VERSION 5.7 ;
  NOWIREEXTENSIONATPIN ON ;
  DIVIDERCHAR "/" ;
  BUSBITCHARS "[]" ;
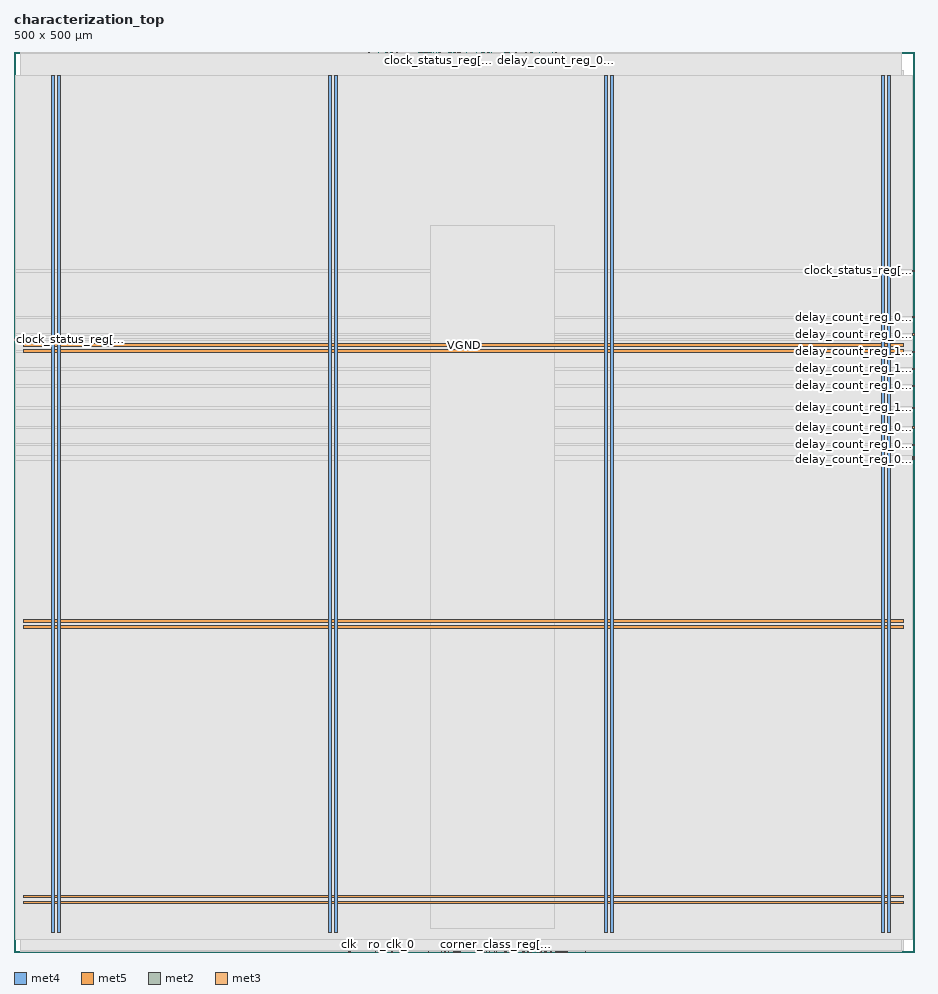
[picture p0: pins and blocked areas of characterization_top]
MACRO characterization_top
  CLASS BLOCK ;
  FOREIGN characterization_top ;
  ORIGIN 0.000 0.000 ;
  SIZE 500.000 BY 500.000 ;
  PIN VGND
    DIRECTION INOUT ;
    USE GROUND ;
    PORT
      LAYER met4 ;
        RECT 24.340 10.640 25.940 487.120 ;
    END
    PORT
      LAYER met4 ;
        RECT 177.940 10.640 179.540 487.120 ;
    END
    PORT
      LAYER met4 ;
        RECT 331.540 10.640 333.140 487.120 ;
    END
    PORT
      LAYER met4 ;
        RECT 485.140 10.640 486.740 487.120 ;
    END
    PORT
      LAYER met5 ;
        RECT 5.520 30.030 494.040 31.630 ;
    END
    PORT
      LAYER met5 ;
        RECT 5.520 183.210 494.040 184.810 ;
    END
    PORT
      LAYER met5 ;
        RECT 5.520 336.390 494.040 337.990 ;
    END
  END VGND
  PIN VPWR
    DIRECTION INOUT ;
    USE POWER ;
    PORT
      LAYER met4 ;
        RECT 21.040 10.640 22.640 487.120 ;
    END
    PORT
      LAYER met4 ;
        RECT 174.640 10.640 176.240 487.120 ;
    END
    PORT
      LAYER met4 ;
        RECT 328.240 10.640 329.840 487.120 ;
    END
    PORT
      LAYER met4 ;
        RECT 481.840 10.640 483.440 487.120 ;
    END
    PORT
      LAYER met5 ;
        RECT 5.520 26.730 494.040 28.330 ;
    END
    PORT
      LAYER met5 ;
        RECT 5.520 179.910 494.040 181.510 ;
    END
    PORT
      LAYER met5 ;
        RECT 5.520 333.090 494.040 334.690 ;
    END
  END VPWR
  PIN busy
    DIRECTION OUTPUT ;
    USE SIGNAL ;
    ANTENNADIFFAREA 0.702900 ;
    PORT
      LAYER met2 ;
        RECT 207.090 499.720 207.370 500.000 ;
    END
  END busy
  PIN clk
    DIRECTION INPUT ;
    USE SIGNAL ;
    ANTENNAGATEAREA 0.852000 ;
    PORT
      LAYER met2 ;
        RECT 185.930 0.000 186.210 0.280 ;
    END
  END clk
  PIN clk_bad_duty
    DIRECTION INPUT ;
    USE SIGNAL ;
    ANTENNAGATEAREA 0.213000 ;
    PORT
      LAYER met2 ;
        RECT 243.890 0.000 244.170 0.280 ;
    END
  END clk_bad_duty
  PIN clk_fast
    DIRECTION INPUT ;
    USE SIGNAL ;
    ANTENNAGATEAREA 0.213000 ;
    PORT
      LAYER met2 ;
        RECT 231.930 499.720 232.210 500.000 ;
    END
  END clk_fast
  PIN clk_slow
    DIRECTION INPUT ;
    USE SIGNAL ;
    ANTENNAGATEAREA 0.213000 ;
    PORT
      LAYER met2 ;
        RECT 244.810 0.000 245.090 0.280 ;
    END
  END clk_slow
  PIN clk_stuck_high
    DIRECTION INPUT ;
    USE SIGNAL ;
    ANTENNAGATEAREA 0.213000 ;
    PORT
      LAYER met2 ;
        RECT 230.090 499.720 230.370 500.000 ;
    END
  END clk_stuck_high
  PIN clk_stuck_low
    DIRECTION INPUT ;
    USE SIGNAL ;
    ANTENNAGATEAREA 0.196500 ;
    PORT
      LAYER met2 ;
        RECT 242.970 499.720 243.250 500.000 ;
    END
  END clk_stuck_low
  PIN clock_status_reg[0]
    DIRECTION OUTPUT ;
    USE SIGNAL ;
    ANTENNADIFFAREA 0.702900 ;
    PORT
      LAYER met2 ;
        RECT 245.730 0.000 246.010 0.280 ;
    END
  END clock_status_reg[0]
  PIN clock_status_reg[1]
    DIRECTION OUTPUT ;
    USE SIGNAL ;
    ANTENNADIFFAREA 0.702900 ;
    PORT
      LAYER met2 ;
        RECT 235.610 499.720 235.890 500.000 ;
    END
  END clock_status_reg[1]
  PIN clock_status_reg[2]
    DIRECTION OUTPUT ;
    USE SIGNAL ;
    ANTENNADIFFAREA 0.702900 ;
    PORT
      LAYER met2 ;
        RECT 246.650 0.000 246.930 0.280 ;
    END
  END clock_status_reg[2]
  PIN clock_status_reg[3]
    DIRECTION OUTPUT ;
    USE SIGNAL ;
    ANTENNADIFFAREA 0.702900 ;
    PORT
      LAYER met2 ;
        RECT 229.170 499.720 229.450 500.000 ;
    END
  END clock_status_reg[3]
  PIN clock_status_reg[4]
    DIRECTION OUTPUT ;
    USE SIGNAL ;
    ANTENNADIFFAREA 0.702900 ;
    PORT
      LAYER met2 ;
        RECT 241.130 0.000 241.410 0.280 ;
    END
  END clock_status_reg[4]
  PIN clock_status_reg[5]
    DIRECTION OUTPUT ;
    USE SIGNAL ;
    ANTENNADIFFAREA 0.702900 ;
    PORT
      LAYER met2 ;
        RECT 231.010 499.720 231.290 500.000 ;
    END
  END clock_status_reg[5]
  PIN clock_status_reg[6]
    DIRECTION OUTPUT ;
    USE SIGNAL ;
    PORT
      LAYER met3 ;
        RECT 499.400 378.120 500.000 378.720 ;
    END
  END clock_status_reg[6]
  PIN clock_status_reg[7]
    DIRECTION OUTPUT ;
    USE SIGNAL ;
    PORT
      LAYER met3 ;
        RECT 0.000 340.040 0.600 340.640 ;
    END
  END clock_status_reg[7]
  PIN corner_class_reg[0]
    DIRECTION OUTPUT ;
    USE SIGNAL ;
    ANTENNADIFFAREA 0.702900 ;
    PORT
      LAYER met2 ;
        RECT 267.810 0.000 268.090 0.280 ;
    END
  END corner_class_reg[0]
  PIN corner_class_reg[1]
    DIRECTION OUTPUT ;
    USE SIGNAL ;
    ANTENNADIFFAREA 0.702900 ;
    PORT
      LAYER met2 ;
        RECT 261.370 0.000 261.650 0.280 ;
    END
  END corner_class_reg[1]
  PIN corner_class_reg[2]
    DIRECTION OUTPUT ;
    USE SIGNAL ;
    ANTENNADIFFAREA 0.702900 ;
    PORT
      LAYER met2 ;
        RECT 266.890 0.000 267.170 0.280 ;
    END
  END corner_class_reg[2]
  PIN delay_count_reg_0[0]
    DIRECTION OUTPUT ;
    USE SIGNAL ;
    ANTENNADIFFAREA 0.702900 ;
    PORT
      LAYER met2 ;
        RECT 226.410 499.720 226.690 500.000 ;
    END
  END delay_count_reg_0[0]
  PIN delay_count_reg_0[10]
    DIRECTION OUTPUT ;
    USE SIGNAL ;
    ANTENNADIFFAREA 0.702900 ;
    PORT
      LAYER met3 ;
        RECT 499.400 352.280 500.000 352.880 ;
    END
  END delay_count_reg_0[10]
  PIN delay_count_reg_0[11]
    DIRECTION OUTPUT ;
    USE SIGNAL ;
    ANTENNADIFFAREA 0.702900 ;
    PORT
      LAYER met2 ;
        RECT 300.930 499.720 301.210 500.000 ;
    END
  END delay_count_reg_0[11]
  PIN delay_count_reg_0[12]
    DIRECTION OUTPUT ;
    USE SIGNAL ;
    ANTENNADIFFAREA 0.702900 ;
    PORT
      LAYER met3 ;
        RECT 499.400 291.080 500.000 291.680 ;
    END
  END delay_count_reg_0[12]
  PIN delay_count_reg_0[13]
    DIRECTION OUTPUT ;
    USE SIGNAL ;
    ANTENNADIFFAREA 0.702900 ;
    PORT
      LAYER met3 ;
        RECT 499.400 281.560 500.000 282.160 ;
    END
  END delay_count_reg_0[13]
  PIN delay_count_reg_0[14]
    DIRECTION OUTPUT ;
    USE SIGNAL ;
    ANTENNADIFFAREA 0.702900 ;
    PORT
      LAYER met3 ;
        RECT 499.400 273.400 500.000 274.000 ;
    END
  END delay_count_reg_0[14]
  PIN delay_count_reg_0[15]
    DIRECTION OUTPUT ;
    USE SIGNAL ;
    ANTENNADIFFAREA 0.702900 ;
    PORT
      LAYER met3 ;
        RECT 499.400 274.760 500.000 275.360 ;
    END
  END delay_count_reg_0[15]
  PIN delay_count_reg_0[1]
    DIRECTION OUTPUT ;
    USE SIGNAL ;
    ANTENNADIFFAREA 0.702900 ;
    PORT
      LAYER met2 ;
        RECT 212.610 499.720 212.890 500.000 ;
    END
  END delay_count_reg_0[1]
  PIN delay_count_reg_0[2]
    DIRECTION OUTPUT ;
    USE SIGNAL ;
    ANTENNADIFFAREA 0.702900 ;
    PORT
      LAYER met2 ;
        RECT 206.170 499.720 206.450 500.000 ;
    END
  END delay_count_reg_0[2]
  PIN delay_count_reg_0[3]
    DIRECTION OUTPUT ;
    USE SIGNAL ;
    ANTENNADIFFAREA 0.702900 ;
    PORT
      LAYER met2 ;
        RECT 227.330 499.720 227.610 500.000 ;
    END
  END delay_count_reg_0[3]
  PIN delay_count_reg_0[4]
    DIRECTION OUTPUT ;
    USE SIGNAL ;
    ANTENNADIFFAREA 0.702900 ;
    PORT
      LAYER met2 ;
        RECT 260.450 499.720 260.730 500.000 ;
    END
  END delay_count_reg_0[4]
  PIN delay_count_reg_0[5]
    DIRECTION OUTPUT ;
    USE SIGNAL ;
    ANTENNADIFFAREA 0.702900 ;
    PORT
      LAYER met2 ;
        RECT 244.810 499.720 245.090 500.000 ;
    END
  END delay_count_reg_0[5]
  PIN delay_count_reg_0[6]
    DIRECTION OUTPUT ;
    USE SIGNAL ;
    ANTENNADIFFAREA 0.702900 ;
    PORT
      LAYER met2 ;
        RECT 272.410 499.720 272.690 500.000 ;
    END
  END delay_count_reg_0[6]
  PIN delay_count_reg_0[7]
    DIRECTION OUTPUT ;
    USE SIGNAL ;
    ANTENNADIFFAREA 0.702900 ;
    PORT
      LAYER met2 ;
        RECT 284.370 499.720 284.650 500.000 ;
    END
  END delay_count_reg_0[7]
  PIN delay_count_reg_0[8]
    DIRECTION OUTPUT ;
    USE SIGNAL ;
    ANTENNADIFFAREA 0.702900 ;
    PORT
      LAYER met3 ;
        RECT 499.400 342.760 500.000 343.360 ;
    END
  END delay_count_reg_0[8]
  PIN delay_count_reg_0[9]
    DIRECTION OUTPUT ;
    USE SIGNAL ;
    ANTENNADIFFAREA 0.702900 ;
    PORT
      LAYER met3 ;
        RECT 499.400 314.200 500.000 314.800 ;
    END
  END delay_count_reg_0[9]
  PIN delay_count_reg_1[0]
    DIRECTION OUTPUT ;
    USE SIGNAL ;
    ANTENNADIFFAREA 0.702900 ;
    PORT
      LAYER met2 ;
        RECT 209.850 499.720 210.130 500.000 ;
    END
  END delay_count_reg_1[0]
  PIN delay_count_reg_1[10]
    DIRECTION OUTPUT ;
    USE SIGNAL ;
    ANTENNADIFFAREA 0.702900 ;
    PORT
      LAYER met2 ;
        RECT 299.090 499.720 299.370 500.000 ;
    END
  END delay_count_reg_1[10]
  PIN delay_count_reg_1[11]
    DIRECTION OUTPUT ;
    USE SIGNAL ;
    ANTENNADIFFAREA 0.702900 ;
    PORT
      LAYER met3 ;
        RECT 499.400 323.720 500.000 324.320 ;
    END
  END delay_count_reg_1[11]
  PIN delay_count_reg_1[12]
    DIRECTION OUTPUT ;
    USE SIGNAL ;
    ANTENNADIFFAREA 0.702900 ;
    PORT
      LAYER met2 ;
        RECT 287.130 0.000 287.410 0.280 ;
    END
  END delay_count_reg_1[12]
  PIN delay_count_reg_1[13]
    DIRECTION OUTPUT ;
    USE SIGNAL ;
    ANTENNADIFFAREA 0.702900 ;
    PORT
      LAYER met2 ;
        RECT 275.170 0.000 275.450 0.280 ;
    END
  END delay_count_reg_1[13]
  PIN delay_count_reg_1[14]
    DIRECTION OUTPUT ;
    USE SIGNAL ;
    ANTENNADIFFAREA 0.702900 ;
    PORT
      LAYER met2 ;
        RECT 317.490 0.000 317.770 0.280 ;
    END
  END delay_count_reg_1[14]
  PIN delay_count_reg_1[15]
    DIRECTION OUTPUT ;
    USE SIGNAL ;
    ANTENNADIFFAREA 0.702900 ;
    PORT
      LAYER met2 ;
        RECT 302.770 0.000 303.050 0.280 ;
    END
  END delay_count_reg_1[15]
  PIN delay_count_reg_1[1]
    DIRECTION OUTPUT ;
    USE SIGNAL ;
    ANTENNADIFFAREA 0.702900 ;
    PORT
      LAYER met2 ;
        RECT 208.930 499.720 209.210 500.000 ;
    END
  END delay_count_reg_1[1]
  PIN delay_count_reg_1[2]
    DIRECTION OUTPUT ;
    USE SIGNAL ;
    ANTENNADIFFAREA 0.702900 ;
    PORT
      LAYER met2 ;
        RECT 234.690 499.720 234.970 500.000 ;
    END
  END delay_count_reg_1[2]
  PIN delay_count_reg_1[3]
    DIRECTION OUTPUT ;
    USE SIGNAL ;
    ANTENNADIFFAREA 0.702900 ;
    PORT
      LAYER met2 ;
        RECT 236.530 499.720 236.810 500.000 ;
    END
  END delay_count_reg_1[3]
  PIN delay_count_reg_1[4]
    DIRECTION OUTPUT ;
    USE SIGNAL ;
    ANTENNADIFFAREA 0.702900 ;
    PORT
      LAYER met2 ;
        RECT 247.570 499.720 247.850 500.000 ;
    END
  END delay_count_reg_1[4]
  PIN delay_count_reg_1[5]
    DIRECTION OUTPUT ;
    USE SIGNAL ;
    ANTENNADIFFAREA 0.702900 ;
    PORT
      LAYER met2 ;
        RECT 259.530 499.720 259.810 500.000 ;
    END
  END delay_count_reg_1[5]
  PIN delay_count_reg_1[6]
    DIRECTION OUTPUT ;
    USE SIGNAL ;
    ANTENNADIFFAREA 0.702900 ;
    PORT
      LAYER met2 ;
        RECT 275.170 499.720 275.450 500.000 ;
    END
  END delay_count_reg_1[6]
  PIN delay_count_reg_1[7]
    DIRECTION OUTPUT ;
    USE SIGNAL ;
    ANTENNADIFFAREA 0.702900 ;
    PORT
      LAYER met2 ;
        RECT 288.050 499.720 288.330 500.000 ;
    END
  END delay_count_reg_1[7]
  PIN delay_count_reg_1[8]
    DIRECTION OUTPUT ;
    USE SIGNAL ;
    ANTENNADIFFAREA 0.702900 ;
    PORT
      LAYER met3 ;
        RECT 499.400 333.240 500.000 333.840 ;
    END
  END delay_count_reg_1[8]
  PIN delay_count_reg_1[9]
    DIRECTION OUTPUT ;
    USE SIGNAL ;
    ANTENNADIFFAREA 0.702900 ;
    PORT
      LAYER met3 ;
        RECT 499.400 301.960 500.000 302.560 ;
    END
  END delay_count_reg_1[9]
  PIN delay_count_reg_2[0]
    DIRECTION OUTPUT ;
    USE SIGNAL ;
    ANTENNADIFFAREA 0.702900 ;
    PORT
      LAYER met2 ;
        RECT 243.890 499.720 244.170 500.000 ;
    END
  END delay_count_reg_2[0]
  PIN delay_count_reg_2[10]
    DIRECTION OUTPUT ;
    USE SIGNAL ;
    ANTENNADIFFAREA 0.702900 ;
    PORT
      LAYER met2 ;
        RECT 274.250 499.720 274.530 500.000 ;
    END
  END delay_count_reg_2[10]
  PIN delay_count_reg_2[11]
    DIRECTION OUTPUT ;
    USE SIGNAL ;
    ANTENNADIFFAREA 0.702900 ;
    PORT
      LAYER met2 ;
        RECT 278.850 499.720 279.130 500.000 ;
    END
  END delay_count_reg_2[11]
  PIN delay_count_reg_2[12]
    DIRECTION OUTPUT ;
    USE SIGNAL ;
    ANTENNADIFFAREA 0.702900 ;
    PORT
      LAYER met2 ;
        RECT 265.050 499.720 265.330 500.000 ;
    END
  END delay_count_reg_2[12]
  PIN delay_count_reg_2[13]
    DIRECTION OUTPUT ;
    USE SIGNAL ;
    ANTENNADIFFAREA 0.702900 ;
    PORT
      LAYER met2 ;
        RECT 263.210 499.720 263.490 500.000 ;
    END
  END delay_count_reg_2[13]
  PIN delay_count_reg_2[14]
    DIRECTION OUTPUT ;
    USE SIGNAL ;
    ANTENNADIFFAREA 0.702900 ;
    PORT
      LAYER met2 ;
        RECT 277.010 0.000 277.290 0.280 ;
    END
  END delay_count_reg_2[14]
  PIN delay_count_reg_2[15]
    DIRECTION OUTPUT ;
    USE SIGNAL ;
    ANTENNADIFFAREA 0.702900 ;
    PORT
      LAYER met2 ;
        RECT 285.290 0.000 285.570 0.280 ;
    END
  END delay_count_reg_2[15]
  PIN delay_count_reg_2[1]
    DIRECTION OUTPUT ;
    USE SIGNAL ;
    ANTENNADIFFAREA 0.702900 ;
    PORT
      LAYER met2 ;
        RECT 228.250 499.720 228.530 500.000 ;
    END
  END delay_count_reg_2[1]
  PIN delay_count_reg_2[2]
    DIRECTION OUTPUT ;
    USE SIGNAL ;
    ANTENNADIFFAREA 0.702900 ;
    PORT
      LAYER met2 ;
        RECT 242.050 499.720 242.330 500.000 ;
    END
  END delay_count_reg_2[2]
  PIN delay_count_reg_2[3]
    DIRECTION OUTPUT ;
    USE SIGNAL ;
    ANTENNADIFFAREA 0.702900 ;
    PORT
      LAYER met2 ;
        RECT 246.650 499.720 246.930 500.000 ;
    END
  END delay_count_reg_2[3]
  PIN delay_count_reg_2[4]
    DIRECTION OUTPUT ;
    USE SIGNAL ;
    ANTENNADIFFAREA 0.702900 ;
    PORT
      LAYER met2 ;
        RECT 261.370 499.720 261.650 500.000 ;
    END
  END delay_count_reg_2[4]
  PIN delay_count_reg_2[5]
    DIRECTION OUTPUT ;
    USE SIGNAL ;
    ANTENNADIFFAREA 0.702900 ;
    PORT
      LAYER met2 ;
        RECT 256.770 499.720 257.050 500.000 ;
    END
  END delay_count_reg_2[5]
  PIN delay_count_reg_2[6]
    DIRECTION OUTPUT ;
    USE SIGNAL ;
    ANTENNADIFFAREA 0.702900 ;
    PORT
      LAYER met2 ;
        RECT 264.130 499.720 264.410 500.000 ;
    END
  END delay_count_reg_2[6]
  PIN delay_count_reg_2[7]
    DIRECTION OUTPUT ;
    USE SIGNAL ;
    ANTENNADIFFAREA 0.702900 ;
    PORT
      LAYER met2 ;
        RECT 273.330 499.720 273.610 500.000 ;
    END
  END delay_count_reg_2[7]
  PIN delay_count_reg_2[8]
    DIRECTION OUTPUT ;
    USE SIGNAL ;
    ANTENNADIFFAREA 0.702900 ;
    PORT
      LAYER met2 ;
        RECT 291.730 499.720 292.010 500.000 ;
    END
  END delay_count_reg_2[8]
  PIN delay_count_reg_2[9]
    DIRECTION OUTPUT ;
    USE SIGNAL ;
    ANTENNADIFFAREA 0.702900 ;
    PORT
      LAYER met2 ;
        RECT 287.130 499.720 287.410 500.000 ;
    END
  END delay_count_reg_2[9]
  PIN done
    DIRECTION OUTPUT ;
    USE SIGNAL ;
    ANTENNADIFFAREA 0.702900 ;
    PORT
      LAYER met2 ;
        RECT 202.490 499.720 202.770 500.000 ;
    END
  END done
  PIN ro_clk_0
    DIRECTION INPUT ;
    USE SIGNAL ;
    ANTENNAGATEAREA 0.213000 ;
    PORT
      LAYER met2 ;
        RECT 209.850 0.000 210.130 0.280 ;
    END
  END ro_clk_0
  PIN ro_clk_1
    DIRECTION INPUT ;
    USE SIGNAL ;
    ANTENNAGATEAREA 0.213000 ;
    PORT
      LAYER met2 ;
        RECT 214.450 0.000 214.730 0.280 ;
    END
  END ro_clk_1
  PIN ro_clk_2
    DIRECTION INPUT ;
    USE SIGNAL ;
    ANTENNAGATEAREA 0.213000 ;
    PORT
      LAYER met2 ;
        RECT 200.650 0.000 200.930 0.280 ;
    END
  END ro_clk_2
  PIN ro_count_reg_0[0]
    DIRECTION OUTPUT ;
    USE SIGNAL ;
    ANTENNADIFFAREA 0.702900 ;
    PORT
      LAYER met2 ;
        RECT 264.130 0.000 264.410 0.280 ;
    END
  END ro_count_reg_0[0]
  PIN ro_count_reg_0[1]
    DIRECTION OUTPUT ;
    USE SIGNAL ;
    ANTENNADIFFAREA 0.702900 ;
    PORT
      LAYER met2 ;
        RECT 282.530 0.000 282.810 0.280 ;
    END
  END ro_count_reg_0[1]
  PIN ro_count_reg_0[2]
    DIRECTION OUTPUT ;
    USE SIGNAL ;
    ANTENNADIFFAREA 0.702900 ;
    PORT
      LAYER met2 ;
        RECT 294.490 0.000 294.770 0.280 ;
    END
  END ro_count_reg_0[2]
  PIN ro_count_reg_0[3]
    DIRECTION OUTPUT ;
    USE SIGNAL ;
    ANTENNADIFFAREA 0.702900 ;
    PORT
      LAYER met2 ;
        RECT 290.810 0.000 291.090 0.280 ;
    END
  END ro_count_reg_0[3]
  PIN ro_count_reg_0[4]
    DIRECTION OUTPUT ;
    USE SIGNAL ;
    ANTENNADIFFAREA 0.702900 ;
    PORT
      LAYER met2 ;
        RECT 300.930 0.000 301.210 0.280 ;
    END
  END ro_count_reg_0[4]
  PIN ro_count_reg_0[5]
    DIRECTION OUTPUT ;
    USE SIGNAL ;
    ANTENNADIFFAREA 0.702900 ;
    PORT
      LAYER met2 ;
        RECT 301.850 0.000 302.130 0.280 ;
    END
  END ro_count_reg_0[5]
  PIN ro_count_reg_0[6]
    DIRECTION OUTPUT ;
    USE SIGNAL ;
    ANTENNADIFFAREA 0.702900 ;
    PORT
      LAYER met2 ;
        RECT 303.690 0.000 303.970 0.280 ;
    END
  END ro_count_reg_0[6]
  PIN ro_count_reg_0[7]
    DIRECTION OUTPUT ;
    USE SIGNAL ;
    ANTENNADIFFAREA 0.702900 ;
    PORT
      LAYER met2 ;
        RECT 277.930 0.000 278.210 0.280 ;
    END
  END ro_count_reg_0[7]
  PIN ro_count_reg_1[0]
    DIRECTION OUTPUT ;
    USE SIGNAL ;
    ANTENNADIFFAREA 0.702900 ;
    PORT
      LAYER met2 ;
        RECT 283.450 0.000 283.730 0.280 ;
    END
  END ro_count_reg_1[0]
  PIN ro_count_reg_1[1]
    DIRECTION OUTPUT ;
    USE SIGNAL ;
    ANTENNADIFFAREA 0.702900 ;
    PORT
      LAYER met2 ;
        RECT 295.410 0.000 295.690 0.280 ;
    END
  END ro_count_reg_1[1]
  PIN ro_count_reg_1[2]
    DIRECTION OUTPUT ;
    USE SIGNAL ;
    ANTENNADIFFAREA 0.702900 ;
    PORT
      LAYER met2 ;
        RECT 304.610 0.000 304.890 0.280 ;
    END
  END ro_count_reg_1[2]
  PIN ro_count_reg_1[3]
    DIRECTION OUTPUT ;
    USE SIGNAL ;
    ANTENNADIFFAREA 0.702900 ;
    PORT
      LAYER met2 ;
        RECT 298.170 0.000 298.450 0.280 ;
    END
  END ro_count_reg_1[3]
  PIN ro_count_reg_1[4]
    DIRECTION OUTPUT ;
    USE SIGNAL ;
    ANTENNADIFFAREA 0.702900 ;
    PORT
      LAYER met2 ;
        RECT 305.530 0.000 305.810 0.280 ;
    END
  END ro_count_reg_1[4]
  PIN ro_count_reg_1[5]
    DIRECTION OUTPUT ;
    USE SIGNAL ;
    ANTENNADIFFAREA 0.702900 ;
    PORT
      LAYER met2 ;
        RECT 291.730 0.000 292.010 0.280 ;
    END
  END ro_count_reg_1[5]
  PIN ro_count_reg_1[6]
    DIRECTION OUTPUT ;
    USE SIGNAL ;
    ANTENNADIFFAREA 0.702900 ;
    PORT
      LAYER met2 ;
        RECT 306.450 0.000 306.730 0.280 ;
    END
  END ro_count_reg_1[6]
  PIN ro_count_reg_1[7]
    DIRECTION OUTPUT ;
    USE SIGNAL ;
    ANTENNADIFFAREA 0.702900 ;
    PORT
      LAYER met2 ;
        RECT 307.370 0.000 307.650 0.280 ;
    END
  END ro_count_reg_1[7]
  PIN ro_count_reg_2[0]
    DIRECTION OUTPUT ;
    USE SIGNAL ;
    ANTENNADIFFAREA 0.702900 ;
    PORT
      LAYER met2 ;
        RECT 230.090 0.000 230.370 0.280 ;
    END
  END ro_count_reg_2[0]
  PIN ro_count_reg_2[1]
    DIRECTION OUTPUT ;
    USE SIGNAL ;
    ANTENNADIFFAREA 0.702900 ;
    PORT
      LAYER met2 ;
        RECT 247.570 0.000 247.850 0.280 ;
    END
  END ro_count_reg_2[1]
  PIN ro_count_reg_2[2]
    DIRECTION OUTPUT ;
    USE SIGNAL ;
    ANTENNADIFFAREA 0.702900 ;
    PORT
      LAYER met2 ;
        RECT 259.530 0.000 259.810 0.280 ;
    END
  END ro_count_reg_2[2]
  PIN ro_count_reg_2[3]
    DIRECTION OUTPUT ;
    USE SIGNAL ;
    ANTENNADIFFAREA 0.702900 ;
    PORT
      LAYER met2 ;
        RECT 260.450 0.000 260.730 0.280 ;
    END
  END ro_count_reg_2[3]
  PIN ro_count_reg_2[4]
    DIRECTION OUTPUT ;
    USE SIGNAL ;
    ANTENNADIFFAREA 0.702900 ;
    PORT
      LAYER met2 ;
        RECT 272.410 0.000 272.690 0.280 ;
    END
  END ro_count_reg_2[4]
  PIN ro_count_reg_2[5]
    DIRECTION OUTPUT ;
    USE SIGNAL ;
    ANTENNADIFFAREA 0.702900 ;
    PORT
      LAYER met2 ;
        RECT 273.330 0.000 273.610 0.280 ;
    END
  END ro_count_reg_2[5]
  PIN ro_count_reg_2[6]
    DIRECTION OUTPUT ;
    USE SIGNAL ;
    ANTENNADIFFAREA 0.702900 ;
    PORT
      LAYER met2 ;
        RECT 276.090 0.000 276.370 0.280 ;
    END
  END ro_count_reg_2[6]
  PIN ro_count_reg_2[7]
    DIRECTION OUTPUT ;
    USE SIGNAL ;
    ANTENNADIFFAREA 0.702900 ;
    PORT
      LAYER met2 ;
        RECT 292.650 0.000 292.930 0.280 ;
    END
  END ro_count_reg_2[7]
  PIN rst
    DIRECTION INPUT ;
    USE SIGNAL ;
    ANTENNAGATEAREA 0.196500 ;
    PORT
      LAYER met2 ;
        RECT 186.850 0.000 187.130 0.280 ;
    END
  END rst
  PIN start
    DIRECTION INPUT ;
    USE SIGNAL ;
    ANTENNAGATEAREA 0.213000 ;
    PORT
      LAYER met2 ;
        RECT 196.970 499.720 197.250 500.000 ;
    END
  END start
  PIN status_reg[0]
    DIRECTION OUTPUT ;
    USE SIGNAL ;
    ANTENNADIFFAREA 0.702900 ;
    PORT
      LAYER met2 ;
        RECT 224.570 499.720 224.850 500.000 ;
    END
  END status_reg[0]
  PIN status_reg[1]
    DIRECTION OUTPUT ;
    USE SIGNAL ;
    ANTENNADIFFAREA 0.702900 ;
    PORT
      LAYER met2 ;
        RECT 225.490 499.720 225.770 500.000 ;
    END
  END status_reg[1]
  PIN status_reg[2]
    DIRECTION OUTPUT ;
    USE SIGNAL ;
    ANTENNADIFFAREA 0.702900 ;
    PORT
      LAYER met2 ;
        RECT 237.450 0.000 237.730 0.280 ;
    END
  END status_reg[2]
  PIN status_reg[3]
    DIRECTION OUTPUT ;
    USE SIGNAL ;
    ANTENNADIFFAREA 0.702900 ;
    PORT
      LAYER met2 ;
        RECT 239.290 0.000 239.570 0.280 ;
    END
  END status_reg[3]
  PIN status_reg[4]
    DIRECTION OUTPUT ;
    USE SIGNAL ;
    ANTENNADIFFAREA 0.702900 ;
    PORT
      LAYER met2 ;
        RECT 232.850 499.720 233.130 500.000 ;
    END
  END status_reg[4]
  PIN status_reg[5]
    DIRECTION OUTPUT ;
    USE SIGNAL ;
    ANTENNADIFFAREA 0.702900 ;
    PORT
      LAYER met2 ;
        RECT 262.290 0.000 262.570 0.280 ;
    END
  END status_reg[5]
  PIN status_reg[6]
    DIRECTION OUTPUT ;
    USE SIGNAL ;
    ANTENNADIFFAREA 0.702900 ;
    PORT
      LAYER met2 ;
        RECT 241.130 499.720 241.410 500.000 ;
    END
  END status_reg[6]
  PIN status_reg[7]
    DIRECTION OUTPUT ;
    USE SIGNAL ;
    ANTENNADIFFAREA 0.702900 ;
    PORT
      LAYER met2 ;
        RECT 251.250 499.720 251.530 500.000 ;
    END
  END status_reg[7]
  OBS
      LAYER nwell ;
        RECT 5.330 10.795 494.230 487.070 ;
      LAYER li1 ;
        RECT 5.520 10.795 494.040 486.965 ;
      LAYER met1 ;
        RECT 3.750 0.720 494.040 489.900 ;
      LAYER met2 ;
        RECT 3.770 499.440 196.690 499.930 ;
        RECT 197.530 499.440 202.210 499.930 ;
        RECT 203.050 499.440 205.890 499.930 ;
        RECT 206.730 499.440 206.810 499.930 ;
        RECT 207.650 499.440 208.650 499.930 ;
        RECT 209.490 499.440 209.570 499.930 ;
        RECT 210.410 499.440 212.330 499.930 ;
        RECT 213.170 499.440 224.290 499.930 ;
        RECT 225.130 499.440 225.210 499.930 ;
        RECT 226.050 499.440 226.130 499.930 ;
        RECT 226.970 499.440 227.050 499.930 ;
        RECT 227.890 499.440 227.970 499.930 ;
        RECT 228.810 499.440 228.890 499.930 ;
        RECT 229.730 499.440 229.810 499.930 ;
        RECT 230.650 499.440 230.730 499.930 ;
        RECT 231.570 499.440 231.650 499.930 ;
        RECT 232.490 499.440 232.570 499.930 ;
        RECT 233.410 499.440 234.410 499.930 ;
        RECT 235.250 499.440 235.330 499.930 ;
        RECT 236.170 499.440 236.250 499.930 ;
        RECT 237.090 499.440 240.850 499.930 ;
        RECT 241.690 499.440 241.770 499.930 ;
        RECT 242.610 499.440 242.690 499.930 ;
        RECT 243.530 499.440 243.610 499.930 ;
        RECT 244.450 499.440 244.530 499.930 ;
        RECT 245.370 499.440 246.370 499.930 ;
        RECT 247.210 499.440 247.290 499.930 ;
        RECT 248.130 499.440 250.970 499.930 ;
        RECT 251.810 499.440 256.490 499.930 ;
        RECT 257.330 499.440 259.250 499.930 ;
        RECT 260.090 499.440 260.170 499.930 ;
        RECT 261.010 499.440 261.090 499.930 ;
        RECT 261.930 499.440 262.930 499.930 ;
        RECT 263.770 499.440 263.850 499.930 ;
        RECT 264.690 499.440 264.770 499.930 ;
        RECT 265.610 499.440 272.130 499.930 ;
        RECT 272.970 499.440 273.050 499.930 ;
        RECT 273.890 499.440 273.970 499.930 ;
        RECT 274.810 499.440 274.890 499.930 ;
        RECT 275.730 499.440 278.570 499.930 ;
        RECT 279.410 499.440 284.090 499.930 ;
        RECT 284.930 499.440 286.850 499.930 ;
        RECT 287.690 499.440 287.770 499.930 ;
        RECT 288.610 499.440 291.450 499.930 ;
        RECT 292.290 499.440 298.810 499.930 ;
        RECT 299.650 499.440 300.650 499.930 ;
        RECT 301.490 499.440 493.030 499.930 ;
        RECT 3.770 0.560 493.030 499.440 ;
        RECT 3.770 0.070 185.650 0.560 ;
        RECT 186.490 0.070 186.570 0.560 ;
        RECT 187.410 0.070 200.370 0.560 ;
        RECT 201.210 0.070 209.570 0.560 ;
        RECT 210.410 0.070 214.170 0.560 ;
        RECT 215.010 0.070 229.810 0.560 ;
        RECT 230.650 0.070 237.170 0.560 ;
        RECT 238.010 0.070 239.010 0.560 ;
        RECT 239.850 0.070 240.850 0.560 ;
        RECT 241.690 0.070 243.610 0.560 ;
        RECT 244.450 0.070 244.530 0.560 ;
        RECT 245.370 0.070 245.450 0.560 ;
        RECT 246.290 0.070 246.370 0.560 ;
        RECT 247.210 0.070 247.290 0.560 ;
        RECT 248.130 0.070 259.250 0.560 ;
        RECT 260.090 0.070 260.170 0.560 ;
        RECT 261.010 0.070 261.090 0.560 ;
        RECT 261.930 0.070 262.010 0.560 ;
        RECT 262.850 0.070 263.850 0.560 ;
        RECT 264.690 0.070 266.610 0.560 ;
        RECT 267.450 0.070 267.530 0.560 ;
        RECT 268.370 0.070 272.130 0.560 ;
        RECT 272.970 0.070 273.050 0.560 ;
        RECT 273.890 0.070 274.890 0.560 ;
        RECT 275.730 0.070 275.810 0.560 ;
        RECT 276.650 0.070 276.730 0.560 ;
        RECT 277.570 0.070 277.650 0.560 ;
        RECT 278.490 0.070 282.250 0.560 ;
        RECT 283.090 0.070 283.170 0.560 ;
        RECT 284.010 0.070 285.010 0.560 ;
        RECT 285.850 0.070 286.850 0.560 ;
        RECT 287.690 0.070 290.530 0.560 ;
        RECT 291.370 0.070 291.450 0.560 ;
        RECT 292.290 0.070 292.370 0.560 ;
        RECT 293.210 0.070 294.210 0.560 ;
        RECT 295.050 0.070 295.130 0.560 ;
        RECT 295.970 0.070 297.890 0.560 ;
        RECT 298.730 0.070 300.650 0.560 ;
        RECT 301.490 0.070 301.570 0.560 ;
        RECT 302.410 0.070 302.490 0.560 ;
        RECT 303.330 0.070 303.410 0.560 ;
        RECT 304.250 0.070 304.330 0.560 ;
        RECT 305.170 0.070 305.250 0.560 ;
        RECT 306.090 0.070 306.170 0.560 ;
        RECT 307.010 0.070 307.090 0.560 ;
        RECT 307.930 0.070 317.210 0.560 ;
        RECT 318.050 0.070 493.030 0.560 ;
      LAYER met3 ;
        RECT 0.600 379.120 499.400 487.045 ;
        RECT 0.600 377.720 499.000 379.120 ;
        RECT 0.600 353.280 499.400 377.720 ;
        RECT 0.600 351.880 499.000 353.280 ;
        RECT 0.600 343.760 499.400 351.880 ;
        RECT 0.600 342.360 499.000 343.760 ;
        RECT 0.600 341.040 499.400 342.360 ;
        RECT 1.000 339.640 499.400 341.040 ;
        RECT 0.600 334.240 499.400 339.640 ;
        RECT 0.600 332.840 499.000 334.240 ;
        RECT 0.600 324.720 499.400 332.840 ;
        RECT 0.600 323.320 499.000 324.720 ;
        RECT 0.600 315.200 499.400 323.320 ;
        RECT 0.600 313.800 499.000 315.200 ;
        RECT 0.600 302.960 499.400 313.800 ;
        RECT 0.600 301.560 499.000 302.960 ;
        RECT 0.600 292.080 499.400 301.560 ;
        RECT 0.600 290.680 499.000 292.080 ;
        RECT 0.600 282.560 499.400 290.680 ;
        RECT 0.600 281.160 499.000 282.560 ;
        RECT 0.600 275.760 499.400 281.160 ;
        RECT 0.600 273.000 499.000 275.760 ;
        RECT 0.600 6.975 499.400 273.000 ;
      LAYER met4 ;
        RECT 231.215 13.095 300.545 403.745 ;
  END
END characterization_top
END LIBRARY

